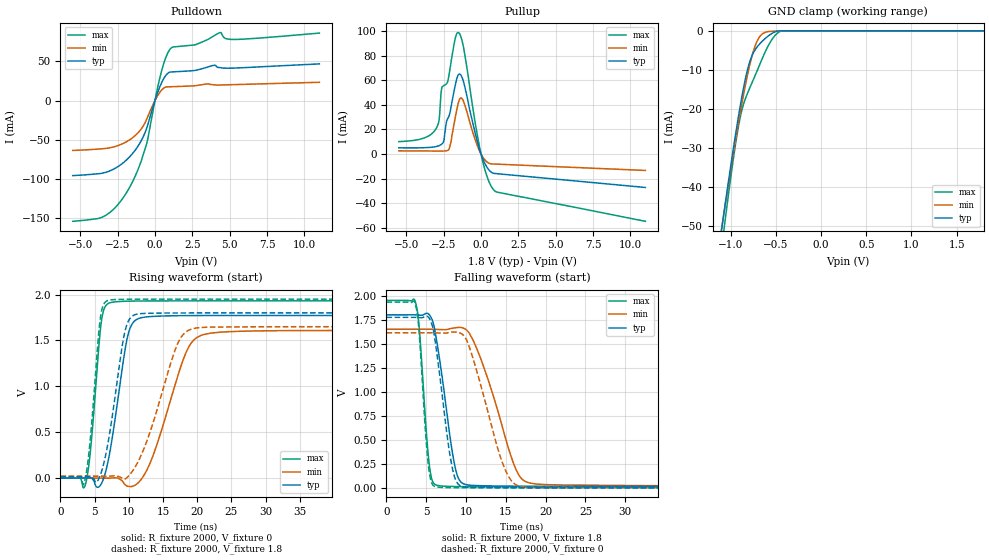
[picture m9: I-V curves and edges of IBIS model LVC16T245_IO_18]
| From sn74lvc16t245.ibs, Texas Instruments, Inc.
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[Model]   LVC16T245_IO_18
Model_type  I/O
Vinl=0.5775
Vinh=1.2675
Enable   Active-Low
Vref =   0
Rref =   2000
Cref =   15p
Vmeas =   0.9
| variable   typ   min   max
C_comp   6.36pF   5.56pF   7.38pF
| C_pullup   10.76pF   6.81pF   16.14pF
| C_pulldown   10.10pF   6.80pF   16.30pF
| C_tri-state   6.36pF   5.56pF   7.38pF
[Temperature Range]   40   100   -40
| Ambient temperature   25   85   -40
[Voltage range]   1.8   1.65   1.95
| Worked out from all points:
|   slope of the pulldown table from 0 to 0.27 V, typ, clamps not added: 18.2 ohm
|   slope of the pullup table from 0 to 0.27 V, typ, clamps not added: 34.2 ohm
|   GND clamp passes 1 mA (typ) near -0.56 V on its own axis
|   rising waveform, R_fixture 2000, V_fixture 0: 20-80 % time 2.1ns typ, 4.04ns min, 1.25ns max; typ from 0 V to 1.77 V
|   falling waveform, R_fixture 2000, V_fixture 1.8: 20-80 % time 1.8ns typ, 3.65ns min, 975ps max; typ from 1.8 V to 0.015 V
|   rising waveform, R_fixture 2000, V_fixture 1.8: 20-80 % time 2.11ns typ, 4.1ns min, 1.24ns max; typ from 0.015 V to 1.8 V
|   falling waveform, R_fixture 2000, V_fixture 0: 20-80 % time 1.65ns typ, 3.23ns min, 921ps max; typ from 1.77 V to 0 V
[GND Clamp]
| LVC16T245_IO_18
|   Voltage   I(typ)   I(min)   I(max)
-5.5V     -897.1mA   -831.9mA   -1.015A
-1.11V    -52.66mA   -52.33mA   -57.72mA
-1.08V    -47.7mA    -47.75mA   -52.14mA
-1.05V    -42.82mA   -43.24mA   -46.67mA
-915mV    -22.23mA   -23.93mA   -24.75mA
-835mV    -12.18mA   -13.81mA   -17.31mA
-785mV    -7.737mA   -8.436mA   -14.47mA
-735mV    -5.102mA   -4.277mA   -11.79mA
-645mV    -2.561mA   -727uA     -6.848mA
-530mV    -501.4uA   -105.7uA   -1.806mA
-430mV    -5.242uA   -35.39uA   -19.91uA
1.8V      23.18pA    30.38nA    510.2pA
[Pulldown]
| LVC16T245_IO_18
|   Voltage   I(typ)   I(min)   I(max)
-5.5V     -95.82mA   -63.67mA   -154.2mA
-3.315V   -91.75mA   -61.14mA   -146.8mA
-1.75V    -72.89mA   -50.79mA   -112.6mA
-1.13V    -58mA      -41.04mA   -87.84mA
-600mV    -37.68mA   -25.69mA   -57.96mA
405mV     21.1mA     12.54mA    35.05mA
770mV     33.15mA    17.47mA    57.09mA
1.105V    36.55mA    17.72mA    67.48mA
2.715V    38.65mA    19.07mA    71.4mA
4.38V     42.01mA    19.88mA    86.86mA
5.235V    41.5mA     20.34mA    78.05mA
11V       46.88mA    23.37mA    86.19mA
[Pullup]
| LVC16T245_IO_18
|   Voltage   I(typ)   I(min)   I(max)
-5.5V     5.088mA    2.627mA    10.09mA
-3.805V   5.165mA    2.515mA    13.04mA
-2.98V    6.16mA     2.455mA    21.15mA
-2.8V     6.846mA    2.441mA    28.18mA
-2.625V   8.108mA    2.443mA    53.57mA
-2.135V   31.01mA    4.02mA     64.57mA
-1.74V    54.87mA    28.55mA    92.96mA
-1.515V   64.43mA    41.57mA    98.64mA
-1.185V   59.29mA    43.25mA    87.57mA
35mV      -1.184mA   -766.3uA   -1.908mA
875mV     -15.72mA   -8.085mA   -29.46mA
11V       -27.14mA   -13.3mA    -54.59mA
[Ramp]
| LVC16T245_IO_18
| variable   typ   min   max
dV/dt_r   1.12/2.25E-09   1.02/4.30E-09   1.22/1.33E-09
dV/dt_f   1.08/1.82E-09   0.99/3.70E-09   1.17/9.83E-10
R_load = 2000
[Rising Waveform]
| LVC16T245_IO_18
R_fixture =   2000
C_fixture =   0
L_fixture =   0
V_fixture =   0
V_fixture_min = 0
V_fixture_max = 0
|   Time   V(typ)   V(min)   V(max)
0s        267.1pV    9.224nV    2.329nV
3.685ns   -81.6uV    27.8nV     -60.59mV
4.445ns   4.317mV    354.9nV    344.6mV
5.93ns    -67.72mV   -28.92uV   1.677V
7.005ns   198.7mV    -195.8uV   1.903V
9.71ns    1.506V     -84.77mV   1.927V
11.25ns   1.733V     -59.41mV   1.929V
18.3ns    1.77V      1.357V     1.931V
20.11ns   1.771V     1.539V     1.931V
50ns      1.772V     1.61V      1.931V
[Falling Waveform]
| LVC16T245_IO_18
R_fixture =   2000
C_fixture =   0
L_fixture =   0
V_fixture =   1.8
V_fixture_min = 1.65
V_fixture_max = 1.95
|   Time   V(typ)   V(min)   V(max)
0s        1.8V       1.65V      1.95V
3.67ns    1.8V       1.65V      1.923V
4.11ns    1.797V     1.65V      1.67V
5.335ns   1.806V     1.65V      272.1mV
6.18ns    1.593V     1.649V     31.35mV
8.47ns    277.9mV    1.663V     14.21mV
9.7ns     41.32mV    1.66V      12.72mV
11.46ns   23.46mV    1.427V     11.67mV
17.47ns   16.85mV    65.44mV    10.43mV
50ns      14.85mV    21.84mV    9.865mV
[Rising Waveform]
| LVC16T245_IO_18
R_fixture =   2000
C_fixture =   0
L_fixture =   0
V_fixture =   1.8
V_fixture_min = 1.65
V_fixture_max = 1.95
|   Time   V(typ)   V(min)   V(max)
0s        14.8mV     21.49mV    9.86mV
3.525ns   14.74mV    21.49mV    -37.29mV
4.325ns   18.68mV    21.49mV    391.7mV
5.775ns   22.28mV    21.47mV    1.708V
6.775ns   310.9mV    21.4mV     1.93V
9.31ns    1.558V     -9.477mV   1.948V
10.74ns   1.776V     99.4mV     1.949V
16.93ns   1.799V     1.427V     1.95V
18.71ns   1.8V       1.61V      1.95V
50ns      1.8V       1.65V      1.95V
[Falling Waveform]
| LVC16T245_IO_18
R_fixture =   2000
C_fixture =   0
L_fixture =   0
V_fixture =   0
V_fixture_min = 0
V_fixture_max = 0
|   Time   V(typ)   V(min)   V(max)
0s        1.774V     1.613V     1.932V
3.635ns   1.774V     1.613V     1.91V
4.075ns   1.771V     1.613V     1.649V
5.23ns    1.78V      1.613V     261.6mV
6.055ns   1.56V      1.612V     15.24mV
8.095ns   282.9mV    1.62V      2.638mV
9.37ns    16.86mV    1.606V     1.782mV
14.54ns   1.59mV     269mV      722.4uV
16.36ns   1.184mV    28.54mV    554.9uV
50ns      52.87uV    209uV      5.159uV
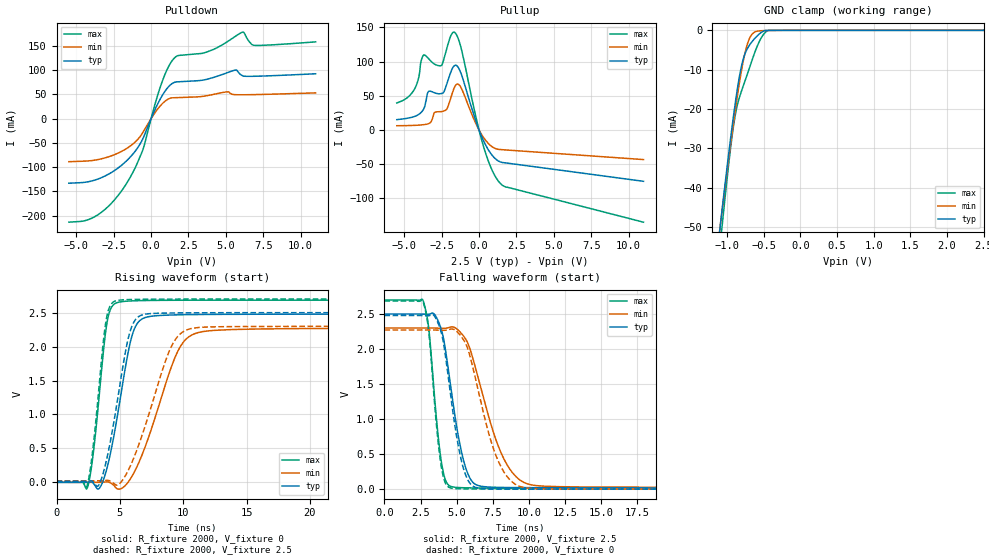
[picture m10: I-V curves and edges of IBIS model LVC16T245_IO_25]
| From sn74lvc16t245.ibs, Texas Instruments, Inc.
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[Model]   LVC16T245_IO_25
Model_type  I/O
Vinl=0.7
Vinh=1.7
Enable   Active-Low
Vref =   0
Rref =   2000
Cref =   15p
Vmeas =   1.25
| variable   typ   min   max
C_comp   6.21pF   5.36pF   7.41pF
| C_pullup   12.67pF   6.54pF   21.33pF
| C_pulldown   9.67pF   6.57pF   15.41pF
| C_tri-state   6.21pF   5.36pF   7.41pF
[Temperature Range]   40   100   -40
| Ambient temperature   25   85   -40
[Voltage range]   2.5   2.3   2.7
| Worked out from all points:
|   slope of the pulldown table from 0 to 0.375 V, typ, clamps not added: 14.3 ohm
|   slope of the pullup table from 0 to 0.375 V, typ, clamps not added: 19.7 ohm
|   GND clamp passes 1 mA (typ) near -0.56 V on its own axis
|   rising waveform, R_fixture 2000, V_fixture 0: 20-80 % time 1.39ns typ, 2.44ns min, 862ps max; typ from 0 V to 2.48 V
|   falling waveform, R_fixture 2000, V_fixture 2.5: 20-80 % time 1.14ns typ, 2.01ns min, 700ps max; typ from 2.5 V to 0.017 V
|   rising waveform, R_fixture 2000, V_fixture 2.5: 20-80 % time 1.37ns typ, 2.37ns min, 846ps max; typ from 0.017 V to 2.5 V
|   falling waveform, R_fixture 2000, V_fixture 0: 20-80 % time 1.07ns typ, 1.75ns min, 675ps max; typ from 2.48 V to 0 V
[GND Clamp]
| LVC16T245_IO_25
|   Voltage   I(typ)   I(min)   I(max)
-5.5V     -897.1mA   -831.9mA   -1.015A
-1.11V    -52.66mA   -52.33mA   -57.72mA
-1.08V    -47.7mA    -47.75mA   -52.14mA
-1.05V    -42.82mA   -43.24mA   -46.67mA
-970mV    -30.27mA   -31.55mA   -32.88mA
-910mV    -21.53mA   -23.26mA   -24.11mA
-825mV    -11.15mA   -12.66mA   -16.7mA
-725mV    -4.734mA   -3.633mA   -11.25mA
-630mV    -2.234mA   -514.4uA   -6.052mA
-515mV    -326.1uA   -90.88uA   -1.362mA
-425mV    -4.501uA   -33.03uA   -11.43uA
2.5V      27.51pA    91.09nA    545.1pA
[Pulldown]
| LVC16T245_IO_25
|   Voltage   I(typ)   I(min)   I(max)
-5.5V     -133.3mA   -88.88mA   -213.8mA
-3.55V    -124.7mA   -84.51mA   -198.3mA
-1.715V   -89.25mA   -63.13mA   -137.4mA
-555mV    -41.71mA   -28.61mA   -64.74mA
300mV     21.24mA    14.01mA    33.98mA
855mV     53.14mA    33.96mA    85.74mA
1.655V    75.71mA    43.25mA    127.8mA
3.765V    81.48mA    47.49mA    138mA
5.655V    100.3mA    49.41mA    170.3mA
6.145V    88.26mA    49.23mA    178.7mA
6.91V     87.46mA    49.58mA    151.3mA
11V       92.57mA    53.16mA    158.4mA
[Pullup]
| LVC16T245_IO_25
|   Voltage   I(typ)   I(min)   I(max)
-5.5V     15.18mA    6.286mA    39.52mA
-4.375V   19.38mA    6.776mA    57.63mA
-3.925V   24.63mA    7.34mA     94.35mA
-3.695V   31.09mA    7.844mA    109.8mA
-3.295V   56.83mA    10.28mA    102.6mA
-2.495V   53.5mA     27.01mA    94.85mA
-2.135V   68.6mA     31.44mA    120.9mA
-1.645V   94.12mA    62.3mA     143.1mA
-1.23V    84.36mA    63.07mA    122.5mA
335mV     -17.24mA   -11.96mA   -26.61mA
1.44V     -46.81mA   -28.58mA   -78.45mA
11V       -75.01mA   -43.22mA   -134.8mA
[Ramp]
| LVC16T245_IO_25
| variable   typ   min   max
dV/dt_r   1.55/1.46E-09   1.42/2.57E-09   1.67/8.99E-10
dV/dt_f   1.50/1.15E-09   1.38/2.02E-09   1.62/7.06E-10
R_load = 2000
[Rising Waveform]
| LVC16T245_IO_25
R_fixture =   2000
C_fixture =   0
L_fixture =   0
V_fixture =   0
V_fixture_min = 0
V_fixture_max = 0
|   Time   V(typ)   V(min)   V(max)
0s        299.6pV    7.204nV    2.034nV
2.455ns   -8.416uV   -5.651uV   -69.42mV
2.935ns   -21.19mV   -30.65uV   481.9mV
3.955ns   190.8mV    6.495mV    2.317V
4.77ns    941.6mV    -94.67mV   2.646V
5.745ns   2V         26.96mV    2.671V
6.405ns   2.349V     253.6mV    2.676V
9.415ns   2.467V     1.869V     2.682V
10.95ns   2.472V     2.193V     2.683V
40ns      2.477V     2.27V      2.684V
[Falling Waveform]
| LVC16T245_IO_25
R_fixture =   2000
C_fixture =   0
L_fixture =   0
V_fixture =   2.5
V_fixture_min = 2.3
V_fixture_max = 2.7
|   Time   V(typ)   V(min)   V(max)
0s        2.5V       2.3V       2.7V
2.7ns     2.499V     2.3V       2.676V
3.08ns    2.497V     2.3V       2.265V
3.925ns   2.286V     2.296V     406.8mV
4.6ns     1.443V     2.315V     38.43mV
5.335ns   527.6mV    2.22V      21.08mV
6.035ns   117.1mV    1.923V     17.81mV
8.025ns   25.06mV    537.6mV    14.19mV
9.895ns   21.85mV    75.16mV    12.97mV
40ns      16.67mV    23.22mV    11.27mV
[Rising Waveform]
| LVC16T245_IO_25
R_fixture =   2000
C_fixture =   0
L_fixture =   0
V_fixture =   2.5
V_fixture_min = 2.3
V_fixture_max = 2.7
|   Time   V(typ)   V(min)   V(max)
0s        16.61mV    22.91mV    11.26mV
2.415ns   16.45mV    22.9mV     -50.74mV
3.28ns    -53.77mV   22.79mV    1.254V
3.87ns    269.1mV    27.65mV    2.333V
4.635ns   1.01V      -33.85mV   2.671V
5.565ns   2.042V     141mV      2.692V
6.2ns     2.389V     408.1mV    2.695V
8.89ns    2.494V     1.93V      2.699V
10.37ns   2.497V     2.252V     2.7V
40ns      2.5V       2.3V       2.7V
[Falling Waveform]
| LVC16T245_IO_25
R_fixture =   2000
C_fixture =   0
L_fixture =   0
V_fixture =   0
V_fixture_min = 0
V_fixture_max = 0
|   Time   V(typ)   V(min)   V(max)
0s        2.478V     2.272V     2.685V
2.695ns   2.477V     2.272V     2.661V
3.065ns   2.475V     2.272V     2.248V
3.885ns   2.267V     2.268V     383.6mV
4.55ns    1.388V     2.283V     18.55mV
5.225ns   497.1mV    2.201V     5.474mV
5.89ns    89.88mV    1.918V     3.825mV
7.695ns   3.207mV    490.1mV    1.939mV
9.435ns   2.451mV    33.5mV     1.252mV
40ns      55.14uV    200.8uV    6.517uV
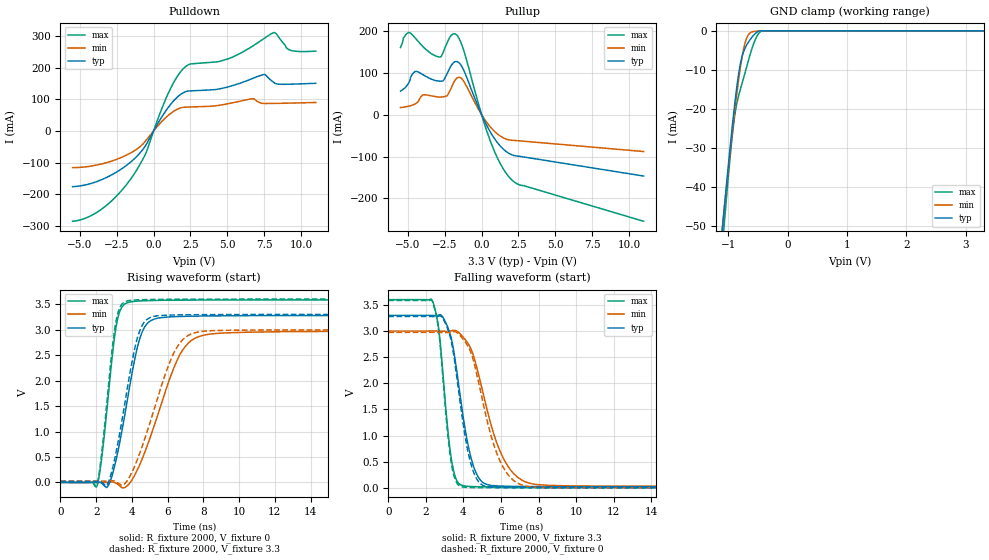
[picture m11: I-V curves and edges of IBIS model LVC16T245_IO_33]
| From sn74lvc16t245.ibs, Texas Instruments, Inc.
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[Model]   LVC16T245_IO_33
Model_type  I/O
Vinl=0.8
Vinh=2.0
Enable   Active-Low
Vref =   0
Rref =   2000
Cref =   15p
Vmeas =   1.5
| variable   typ   min   max
C_comp   6.07pF   5.16pF   7.44pF
| C_pullup   14.04pF   6.24pF   25.25pF
| C_pulldown   9.25pF   6.40pF   14.82pF
| C_tri-state   6.07pF   5.16pF   7.44pF
[Temperature Range]   40   100   -40
| Ambient temperature   25   85   -40
[Voltage range]   3.3   3   3.6
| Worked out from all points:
|   slope of the pulldown table from 0 to 0.495 V, typ, clamps not added: 12.4 ohm
|   slope of the pullup table from 0 to 0.495 V, typ, clamps not added: 14 ohm
|   GND clamp passes 1 mA (typ) near -0.56 V on its own axis
|   rising waveform, R_fixture 2000, V_fixture 0: 20-80 % time 1.04ns typ, 1.78ns min, 644ps max; typ from 0 V to 3.28 V
|   falling waveform, R_fixture 2000, V_fixture 3.3: 20-80 % time 864ps typ, 1.42ns min, 553ps max; typ from 3.3 V to 0.019 V
|   rising waveform, R_fixture 2000, V_fixture 3.3: 20-80 % time 1.01ns typ, 1.68ns min, 627ps max; typ from 0.019 V to 3.3 V
|   falling waveform, R_fixture 2000, V_fixture 0: 20-80 % time 819ps typ, 1.28ns min, 536ps max; typ from 3.28 V to 0 V
[GND Clamp]
| LVC16T245_IO_33
|   Voltage   I(typ)   I(min)   I(max)
-5.5V     -897.1mA   -831.9mA   -1.015A
-1.095V   -50.17mA   -50.04mA   -54.92mA
-1.065V   -45.25mA   -45.49mA   -49.39mA
-970mV    -30.27mA   -31.55mA   -32.88mA
-905mV    -20.84mA   -22.59mA   -23.49mA
-860mV    -15.02mA   -16.81mA   -19.04mA
-790mV    -8.096mA   -8.927mA   -14.74mA
-735mV    -5.102mA   -4.277mA   -11.79mA
-675mV    -3.272mA   -1.404mA   -8.498mA
-560mV    -930.2uA   -146.6uA   -2.855mA
-455mV    -11.08uA   -48.45uA   -188.9uA
3.3V      32.42pA    190.2nA    586.5pA
[Pulldown]
| LVC16T245_IO_33
|   Voltage   I(typ)   I(min)   I(max)
-5.5V     -176.2mA   -116.1mA   -285.6mA
-3.56V    -154.7mA   -104.8mA   -248.1mA
-1.62V    -100.7mA   -71.19mA   -156.1mA
-535mV    -45.52mA   -31.12mA   -71.38mA
1.155V    84.06mA    55.16mA    134.7mA
2.23V     124.7mA    75.07mA    205.2mA
5.1V      139.6mA    86.34mA    228.5mA
6.75V     166.1mA    101.8mA    268.8mA
7.495V    178.1mA    86.65mA    292mA
8.17V     152.3mA    86.77mA    310.5mA
9.2V      147.4mA    87.68mA    256mA
11V       150.3mA    89.74mA    251.8mA
[Pullup]
| LVC16T245_IO_33
|   Voltage   I(typ)   I(min)   I(max)
-5.5V     56.18mA    16.98mA    160.3mA
-4.89V    79.66mA    20.64mA    195.7mA
-4.445V   103.3mA    26.89mA    180.5mA
-3.945V   94.62mA    47.4mA     161.1mA
-2.805V   79.84mA    41.85mA    137.4mA
-2.095V   114.9mA    61.02mA    187.6mA
-1.66V    126.5mA    87.57mA    189.1mA
-1.24V    108mA      81.18mA    156.3mA
695mV     -47.39mA   -33.41mA   -72.26mA
1.475V    -82.35mA   -55.39mA   -129.6mA
2.255V    -98mA      -61.58mA   -161.7mA
11V       -146.5mA   -88.02mA   -254.5mA
[Ramp]
| LVC16T245_IO_33
| variable   typ   min   max
dV/dt_r   2.03/1.08E-09   1.85/1.85E-09   2.20/6.61E-10
dV/dt_f   1.98/8.69E-10   1.79/1.43E-09   2.16/5.57E-10
R_load = 2000
[Rising Waveform]
| LVC16T245_IO_33
R_fixture =   2000
C_fixture =   0
L_fixture =   0
V_fixture =   0
V_fixture_min = 0
V_fixture_max = 0
|   Time   V(typ)   V(min)   V(max)
0s        346pV      6.356nV    1.892nV
2.055ns   1.062mV    -1.408uV   -62.11mV
2.61ns    -93.59mV   109.1uV    1.46V
3.11ns    438.4mV    -15.03mV   3.049V
3.785ns   1.702V     -50.66mV   3.534V
4.345ns   2.708V     277mV      3.562V
4.855ns   3.119V     719.4mV    3.57V
6.615ns   3.259V     2.462V     3.58V
7.89ns    3.268V     2.88V      3.582V
34.99ns   3.279V     2.973V     3.584V
[Falling Waveform]
| LVC16T245_IO_33
R_fixture =   2000
C_fixture =   0
L_fixture =   0
V_fixture =   3.3
V_fixture_min = 3
V_fixture_max = 3.6
|   Time   V(typ)   V(min)   V(max)
0s        3.3V       3V         3.6V
2.36ns    3.298V     3V         3.569V
2.705ns   3.309V     2.999V     2.974V
3.365ns   2.842V     3.004V     531.1mV
3.94ns    1.471V     2.902V     45.57mV
4.415ns   559.8mV    2.646V     25.81mV
4.92ns    140.7mV    2.003V     20.96mV
6.09ns    32.87mV    593.7mV    17.93mV
7.535ns   25.55mV    87.18mV    15.91mV
34.99ns   19.26mV    26.22mV    13.14mV
[Rising Waveform]
| LVC16T245_IO_33
R_fixture =   2000
C_fixture =   0
L_fixture =   0
V_fixture =   3.3
V_fixture_min = 3
V_fixture_max = 3.6
|   Time   V(typ)   V(min)   V(max)
0s        19.2mV     25.88mV    13.13mV
2.04ns    19.85mV    25.88mV    -42.2mV
2.6ns     -52.48mV   25.93mV    1.571V
3.065ns   511.1mV    19.55mV    3.077V
3.725ns   1.808V     27.13mV    3.563V
4.255ns   2.772V     404.1mV    3.585V
4.735ns   3.165V     875.1mV    3.591V
6.32ns    3.288V     2.524V     3.597V
7.525ns   3.294V     2.94V      3.599V
34.99ns   3.3V       3V         3.6V
[Falling Waveform]
| LVC16T245_IO_33
R_fixture =   2000
C_fixture =   0
L_fixture =   0
V_fixture =   0
V_fixture_min = 0
V_fixture_max = 0
|   Time   V(typ)   V(min)   V(max)
0s        3.279V     2.974V     3.585V
2.36ns    3.277V     2.974V     3.552V
2.695ns   3.287V     2.973V     2.959V
3.335ns   2.833V     2.976V     514.9mV
3.88ns    1.486V     2.89V      24.97mV
4.335ns   545mV      2.643V     7.235mV
4.815ns   113.9mV    2.009V     4.039mV
5.91ns    5.918mV    545.7mV    2.92mV
7.23ns    2.311mV    40.82mV    1.853mV
34.99ns   59.16uV    216.9uV    7.377uV
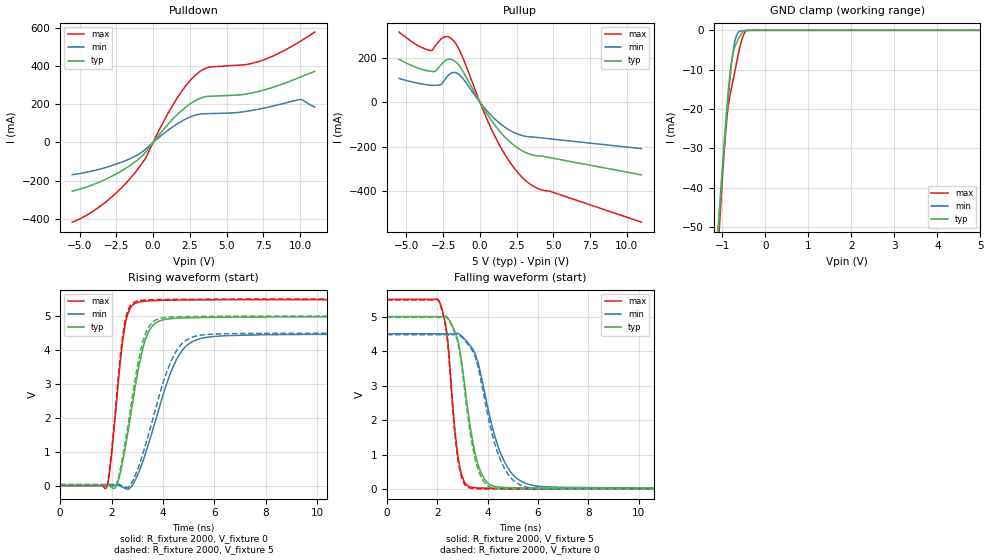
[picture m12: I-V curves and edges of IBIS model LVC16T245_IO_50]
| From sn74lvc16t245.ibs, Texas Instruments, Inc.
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[Model]   LVC16T245_IO_50
Model_type  I/O
Vinl=1.35
Vinh=3.85
Enable   Active-Low
Vref =   0
Rref =   2000
Cref =   15p
Vmeas =   2.5
| variable   typ   min   max
C_comp   5.81pF   4.85pF   7.40pF
| C_pullup   14.65pF   5.92pF   27.87pF
| C_pulldown   8.71pF   6.16pF   14.29pF
| C_tri-state   5.81pF   4.85pF   7.40pF
[Temperature Range]   40   100   -40
| Ambient temperature   25   85   -40
[Voltage range]   5   4.5   5.5
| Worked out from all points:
|   slope of the pulldown table from 0 to 0.75 V, typ, clamps not added: 10.5 ohm
|   slope of the pullup table from 0 to 0.75 V, typ, clamps not added: 9.47 ohm
|   GND clamp passes 1 mA (typ) near -0.56 V on its own axis
|   rising waveform, R_fixture 2000, V_fixture 0: 20-80 % time 695ps typ, 1.14ns min, 432ps max; typ from 0 V to 4.98 V
|   falling waveform, R_fixture 2000, V_fixture 5: 20-80 % time 607ps typ, 946ps min, 393ps max; typ from 5 V to 0.025 V
|   rising waveform, R_fixture 2000, V_fixture 5: 20-80 % time 667ps typ, 1.07ns min, 419ps max; typ from 0.025 V to 5 V
|   falling waveform, R_fixture 2000, V_fixture 0: 20-80 % time 583ps typ, 879ps min, 383ps max; typ from 4.98 V to 0 V
[GND Clamp]
| LVC16T245_IO_50
|   Voltage   I(typ)   I(min)   I(max)
-5.5V     -897.1mA   -831.9mA   -1.015A
-1.115V   -53.49mA   -53.1mA    -58.66mA
-1.08V    -47.7mA    -47.75mA   -52.14mA
-1.05V    -42.82mA   -43.24mA   -46.67mA
-915mV    -22.23mA   -23.93mA   -24.75mA
-870mV    -16.24mA   -18.06mA   -19.86mA
-810mV    -9.725mA   -11mA      -15.84mA
-710mV    -4.241mA   -2.794mA   -10.43mA
-595mV    -1.535mA   -238.1uA   -4.333mA
-495mV    -143.9uA   -74.43uA   -859.9uA
-410mV    -2.841uA   -26.45uA   -7.398uA
5V        42.75pA    201.5nA    680.2pA
[Pulldown]
| LVC16T245_IO_50
|   Voltage   I(typ)   I(min)   I(max)
-5.5V     -253.8mA   -167.8mA   -415.9mA
-3.43V    -199.2mA   -134.9mA   -323mA
-1.42V    -112.1mA   -79.11mA   -175.4mA
-515mV    -51.25mA   -34.88mA   -81.44mA
675mV     64.66mA    43.62mA    103.8mA
1.605V    142.3mA    95.28mA    227.8mA
2.375V    193.6mA    128.1mA    310mA
3.085V    226.9mA    146.6mA    364.6mA
3.83V     241.1mA    150.7mA    393.4mA
7.4V      270.6mA    177.1mA    427.6mA
10.03V    341.2mA    224.3mA    528.3mA
11V       371.1mA    184.2mA    576.2mA
[Pullup]
| LVC16T245_IO_50
|   Voltage   I(typ)   I(min)   I(max)
-5.5V     192.6mA    106.5mA    315.1mA
-3.39V    139mA      76.44mA    232.1mA
-3.02V    139.4mA    75.83mA    254.6mA
-2.445V   182.3mA    95.48mA    292.9mA
-1.78V    187.3mA    133.5mA    275.4mA
-1.265V   150.4mA    114.7mA    215.4mA
270mV     -30.29mA   -22.56mA   -44.29mA
1.205V    -119.5mA   -87.17mA   -177.6mA
2.245V    -190.4mA   -134.4mA   -289.3mA
3.285V    -231.3mA   -155.7mA   -362.5mA
4.095V    -242.4mA   -160.5mA   -392.8mA
11V       -327.5mA   -209.3mA   -540.4mA
[Ramp]
| LVC16T245_IO_50
| variable   typ   min   max
dV/dt_r   3.04/7.06E-10   2.75/1.17E-09   3.34/4.38E-10
dV/dt_f   2.99/6.11E-10   2.69/9.52E-10   3.29/3.95E-10
R_load = 2000
[Rising Waveform]
| LVC16T245_IO_50
R_fixture =   2000
C_fixture =   0
L_fixture =   0
V_fixture =   0
V_fixture_min = 0
V_fixture_max = 0
|   Time   V(typ)   V(min)   V(max)
0s        447.4pV    5.606nV    1.8nV
1.815ns   4.17mV     -89.25uV   -46.21mV
2.185ns   -21.39mV   8.135mV    2.403V
2.515ns   1.047V     -78.97mV   4.686V
2.73ns    2.016V     -59.62mV   5.234V
3.075ns   3.562V     424.2mV    5.413V
3.56ns    4.683V     1.535V     5.452V
4.46ns    4.931V     3.614V     5.47V
5.545ns   4.957V     4.352V     5.477V
29.99ns   4.978V     4.473V     5.483V
[Falling Waveform]
| LVC16T245_IO_50
R_fixture =   2000
C_fixture =   0
L_fixture =   0
V_fixture =   5
V_fixture_min = 4.5
V_fixture_max = 5.5
|   Time   V(typ)   V(min)   V(max)
0s        5V         4.5V       5.5V
2.085ns   4.997V     4.5V       5.429V
2.39ns    4.982V     4.497V     4.46V
2.685ns   4.588V     4.508V     1.832V
2.855ns   4.189V     4.496V     799.4mV
3.34ns    1.671V     4.13V      58.42mV
3.815ns   366.5mV    3.037V     31.37mV
4.58ns    52.15mV    935.9mV    24.16mV
5.77ns    34.67mV    112mV      21.04mV
29.99ns   24.92mV    33.45mV    17.03mV
[Rising Waveform]
| LVC16T245_IO_50
R_fixture =   2000
C_fixture =   0
L_fixture =   0
V_fixture =   5
V_fixture_min = 4.5
V_fixture_max = 5.5
|   Time   V(typ)   V(min)   V(max)
0s        24.84mV    32.98mV    17.02mV
1.815ns   29.01mV    32.89mV    -18.11mV
2.175ns   17.02mV    40.16mV    2.473V
2.49ns    1.1V       -34.21mV   4.709V
2.695ns   2.066V     -12.05mV   5.263V
3.015ns   3.559V     482mV      5.443V
3.48ns    4.718V     1.626V     5.477V
4.32ns    4.969V     3.68V      5.49V
5.35ns    4.987V     4.424V     5.495V
29.99ns   5V         4.5V       5.5V
[Falling Waveform]
| LVC16T245_IO_50
R_fixture =   2000
C_fixture =   0
L_fixture =   0
V_fixture =   0
V_fixture_min = 0
V_fixture_max = 0
|   Time   V(typ)   V(min)   V(max)
0s        4.979V     4.474V     5.484V
2.085ns   4.975V     4.475V     5.411V
2.39ns    4.958V     4.471V     4.404V
2.67ns    4.575V     4.479V     1.831V
2.84ns    4.171V     4.474V     763.7mV
3.3ns     1.694V     4.119V     32.08mV
3.76ns    329.3mV    3.063V     7.889mV
4.5ns     14.18mV    870.6mV    3.433mV
5.58ns    3.64mV     53.11mV    1.988mV
29.99ns   75.97uV    272.5uV    10.17uV
